VERSION 5.7 ;
  NOWIREEXTENSIONATPIN ON ;
  DIVIDERCHAR "/" ;
  BUSBITCHARS "[]" ;
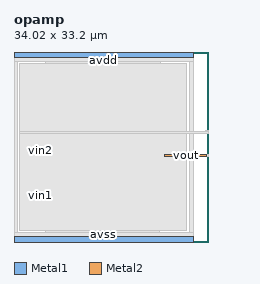
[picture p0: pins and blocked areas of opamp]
MACRO opamp
  CLASS BLOCK ;
  FOREIGN opamp ;
  ORIGIN 0.000 0.000 ;
  SIZE 34.020 BY 33.200 ;
  PIN avss
    USE GROUND ;
    PORT
      LAYER Metal1 ;
        RECT 0.000 0.000 31.400 1.000 ;
    END
  END avss
  PIN avdd
    USE POWER ;
    PORT
      LAYER Metal1 ;
        RECT 0.000 32.200 31.400 33.200 ;
    END
  END avdd
  PIN vout
    ANTENNADIFFAREA 10.568000 ;
    PORT
      LAYER Metal2 ;
        RECT 26.385 14.925 33.610 15.275 ;
    END
  END vout
  PIN vin2
    ANTENNAGATEAREA 5.000000 ;
    PORT
      LAYER Metal2 ;
        RECT 4.090 15.455 5.220 16.540 ;
    END
  END vin2
  PIN vin1
    ANTENNAGATEAREA 5.000000 ;
    PORT
      LAYER Metal2 ;
        RECT 3.935 7.435 5.225 8.720 ;
    END
  END vin1
  OBS
      LAYER Nwell ;
        RECT 13.490 26.500 17.875 26.540 ;
        RECT 21.060 26.500 25.000 26.540 ;
        RECT 13.490 26.410 25.000 26.500 ;
        RECT 12.860 26.300 25.000 26.410 ;
        RECT 6.790 23.690 25.000 26.300 ;
        RECT 6.790 22.520 25.020 23.690 ;
        RECT 6.790 15.800 24.960 22.520 ;
        RECT 6.790 15.200 14.145 15.800 ;
      LAYER Pwell ;
        RECT 6.300 4.180 9.800 14.280 ;
        RECT 10.215 7.070 13.715 14.170 ;
        RECT 14.045 7.090 17.545 14.190 ;
        RECT 17.735 4.215 21.235 13.315 ;
        RECT 21.495 4.290 24.995 14.390 ;
      LAYER Metal1 ;
        RECT 5.585 26.410 25.645 32.200 ;
        RECT 6.110 26.085 25.260 26.410 ;
        RECT 6.110 25.885 18.150 26.085 ;
        RECT 6.110 25.180 7.205 25.885 ;
        RECT 8.050 25.415 9.030 25.645 ;
        RECT 7.665 25.180 7.895 25.240 ;
        RECT 4.090 15.455 5.220 16.540 ;
        RECT 6.110 16.325 7.895 25.180 ;
        RECT 9.185 16.530 9.415 25.240 ;
        RECT 9.875 25.200 10.105 25.885 ;
        RECT 10.950 25.415 11.930 25.645 ;
        RECT 12.775 25.400 18.150 25.885 ;
        RECT 19.175 25.845 20.355 25.850 ;
        RECT 18.995 25.615 20.355 25.845 ;
        RECT 20.125 25.440 20.355 25.615 ;
        RECT 18.610 25.400 18.840 25.440 ;
        RECT 10.565 25.200 10.795 25.240 ;
        RECT 6.110 15.615 7.205 16.325 ;
        RECT 7.665 16.260 7.895 16.325 ;
        RECT 8.385 16.235 8.750 16.260 ;
        RECT 9.140 16.235 9.420 16.530 ;
        RECT 8.385 16.085 9.420 16.235 ;
        RECT 8.050 15.955 9.420 16.085 ;
        RECT 9.875 16.335 10.830 25.200 ;
        RECT 12.085 16.935 12.315 25.240 ;
        RECT 12.775 24.550 18.850 25.400 ;
        RECT 20.125 24.600 20.360 25.440 ;
        RECT 12.775 23.815 18.150 24.550 ;
        RECT 18.610 24.460 18.840 24.550 ;
        RECT 19.295 24.295 19.780 24.540 ;
        RECT 20.120 24.460 20.360 24.600 ;
        RECT 20.120 24.295 20.355 24.460 ;
        RECT 19.295 24.285 20.355 24.295 ;
        RECT 18.995 24.065 20.355 24.285 ;
        RECT 18.995 24.055 19.975 24.065 ;
        RECT 20.820 23.815 25.260 26.085 ;
        RECT 12.775 23.690 25.260 23.815 ;
        RECT 12.775 22.375 25.315 23.690 ;
        RECT 12.775 22.285 24.775 22.375 ;
        RECT 12.775 21.550 14.275 22.285 ;
        RECT 15.120 21.815 16.100 22.045 ;
        RECT 16.640 21.815 17.620 22.045 ;
        RECT 18.160 21.815 19.140 22.045 ;
        RECT 19.680 21.815 20.660 22.045 ;
        RECT 21.200 21.815 22.180 22.045 ;
        RECT 22.720 21.815 23.700 22.045 ;
        RECT 14.735 21.550 14.965 21.640 ;
        RECT 12.775 21.400 14.965 21.550 ;
        RECT 12.775 20.835 15.195 21.400 ;
        RECT 12.030 16.410 12.445 16.935 ;
        RECT 12.775 16.900 14.965 20.835 ;
        RECT 16.255 18.050 16.485 21.640 ;
        RECT 17.775 21.355 18.005 21.640 ;
        RECT 17.660 20.790 18.255 21.355 ;
        RECT 16.160 17.560 16.550 18.050 ;
        RECT 8.050 15.855 9.030 15.955 ;
        RECT 9.875 15.615 10.105 16.335 ;
        RECT 10.565 16.260 10.795 16.335 ;
        RECT 11.140 16.085 11.545 16.270 ;
        RECT 12.085 16.260 12.315 16.410 ;
        RECT 12.775 16.215 14.275 16.900 ;
        RECT 14.735 16.860 14.965 16.900 ;
        RECT 15.345 16.685 15.760 16.985 ;
        RECT 16.255 16.860 16.485 17.560 ;
        RECT 16.715 16.685 17.250 16.905 ;
        RECT 17.775 16.860 18.005 20.790 ;
        RECT 19.295 18.050 19.525 21.640 ;
        RECT 20.815 21.380 21.045 21.640 ;
        RECT 20.675 20.815 21.270 21.380 ;
        RECT 19.170 17.565 19.595 18.050 ;
        RECT 18.440 16.870 18.825 16.910 ;
        RECT 18.400 16.685 18.865 16.870 ;
        RECT 19.295 16.860 19.525 17.565 ;
        RECT 19.925 16.685 20.335 16.925 ;
        RECT 20.815 16.860 21.045 20.815 ;
        RECT 22.335 18.025 22.565 21.640 ;
        RECT 23.855 21.600 24.085 21.640 ;
        RECT 24.545 21.600 24.775 22.285 ;
        RECT 22.205 17.580 22.695 18.025 ;
        RECT 21.495 16.685 21.905 16.925 ;
        RECT 22.335 16.860 22.565 17.580 ;
        RECT 23.850 16.950 24.800 21.600 ;
        RECT 23.025 16.685 23.475 16.925 ;
        RECT 23.855 16.860 24.085 16.950 ;
        RECT 15.120 16.455 16.100 16.685 ;
        RECT 16.640 16.455 17.620 16.685 ;
        RECT 18.160 16.455 19.140 16.685 ;
        RECT 19.680 16.455 20.660 16.685 ;
        RECT 21.200 16.455 22.180 16.685 ;
        RECT 22.720 16.455 23.700 16.685 ;
        RECT 15.360 16.445 15.745 16.455 ;
        RECT 18.440 16.445 18.825 16.455 ;
        RECT 19.925 16.445 20.335 16.455 ;
        RECT 21.495 16.445 21.905 16.455 ;
        RECT 23.025 16.445 23.475 16.455 ;
        RECT 24.545 16.215 24.775 16.950 ;
        RECT 10.950 15.855 11.930 16.085 ;
        RECT 12.775 16.000 24.775 16.215 ;
        RECT 12.775 15.615 13.005 16.000 ;
        RECT 14.045 15.985 24.775 16.000 ;
        RECT 6.110 15.385 13.005 15.615 ;
        RECT 6.110 15.370 7.090 15.385 ;
        RECT 25.310 14.690 26.385 15.695 ;
        RECT 6.485 14.090 9.615 14.095 ;
        RECT 6.485 14.075 10.575 14.090 ;
        RECT 5.550 13.985 10.575 14.075 ;
        RECT 13.455 14.005 14.560 14.075 ;
        RECT 13.455 13.985 17.360 14.005 ;
        RECT 5.550 13.865 17.360 13.985 ;
        RECT 5.550 13.070 6.715 13.865 ;
        RECT 9.385 13.775 17.360 13.865 ;
        RECT 9.385 13.755 14.560 13.775 ;
        RECT 7.560 13.395 8.540 13.625 ;
        RECT 7.755 13.235 8.270 13.395 ;
        RECT 7.175 13.070 7.405 13.220 ;
        RECT 3.940 8.720 5.215 8.730 ;
        RECT 3.935 7.435 5.225 8.720 ;
        RECT 5.550 5.300 7.405 13.070 ;
        RECT 5.550 4.695 6.715 5.300 ;
        RECT 7.175 5.240 7.405 5.300 ;
        RECT 7.805 5.295 8.190 13.235 ;
        RECT 8.695 11.345 8.925 13.220 ;
        RECT 8.540 10.895 8.980 11.345 ;
        RECT 7.805 5.065 8.355 5.295 ;
        RECT 8.695 5.240 8.925 10.895 ;
        RECT 9.385 7.485 10.630 13.755 ;
        RECT 11.475 13.285 12.455 13.515 ;
        RECT 11.090 11.360 11.320 13.110 ;
        RECT 12.610 12.325 12.840 13.110 ;
        RECT 12.545 12.000 12.950 12.325 ;
        RECT 11.090 10.880 11.535 11.360 ;
        RECT 11.090 8.130 11.320 10.880 ;
        RECT 11.615 7.955 12.145 8.290 ;
        RECT 12.610 8.130 12.840 12.000 ;
        RECT 11.475 7.725 12.455 7.955 ;
        RECT 13.300 7.505 14.560 13.755 ;
        RECT 15.305 13.305 16.285 13.535 ;
        RECT 14.920 11.345 15.150 13.130 ;
        RECT 16.440 12.555 16.670 13.130 ;
        RECT 16.355 12.040 16.790 12.555 ;
        RECT 14.920 10.895 15.360 11.345 ;
        RECT 14.920 8.150 15.150 10.895 ;
        RECT 15.525 7.975 16.035 8.165 ;
        RECT 16.440 8.150 16.670 12.040 ;
        RECT 15.305 7.745 16.285 7.975 ;
        RECT 15.525 7.735 16.035 7.745 ;
        RECT 17.130 7.505 17.360 13.775 ;
        RECT 21.680 13.975 24.810 14.205 ;
        RECT 13.300 7.485 17.360 7.505 ;
        RECT 9.385 7.440 17.360 7.485 ;
        RECT 17.920 12.900 21.050 13.130 ;
        RECT 21.680 13.120 21.910 13.975 ;
        RECT 22.755 13.505 23.735 13.735 ;
        RECT 22.370 13.120 22.600 13.330 ;
        RECT 17.920 12.060 18.150 12.900 ;
        RECT 18.995 12.430 19.975 12.660 ;
        RECT 18.610 12.060 18.840 12.255 ;
        RECT 17.920 7.440 18.840 12.060 ;
        RECT 20.130 11.720 20.360 12.255 ;
        RECT 20.030 11.230 20.440 11.720 ;
        RECT 9.385 5.505 18.840 7.440 ;
        RECT 7.560 4.835 8.540 5.065 ;
        RECT 5.505 4.595 6.780 4.695 ;
        RECT 9.385 4.630 18.150 5.505 ;
        RECT 18.610 5.275 18.840 5.505 ;
        RECT 19.305 5.100 19.695 5.355 ;
        RECT 20.130 5.275 20.360 11.230 ;
        RECT 18.995 4.870 19.975 5.100 ;
        RECT 19.305 4.860 19.695 4.870 ;
        RECT 20.820 4.695 21.050 12.900 ;
        RECT 21.665 5.455 22.600 13.120 ;
        RECT 23.890 5.600 24.120 13.330 ;
        RECT 23.350 5.515 24.150 5.600 ;
        RECT 21.680 4.705 21.910 5.455 ;
        RECT 22.370 5.350 22.600 5.455 ;
        RECT 22.950 5.175 24.150 5.515 ;
        RECT 22.755 5.000 24.150 5.175 ;
        RECT 22.755 4.945 23.735 5.000 ;
        RECT 24.580 4.705 24.810 13.975 ;
        RECT 21.680 4.695 24.810 4.705 ;
        RECT 20.820 4.630 25.415 4.695 ;
        RECT 9.385 4.595 25.415 4.630 ;
        RECT 5.505 1.000 25.415 4.595 ;
      LAYER Metal2 ;
        RECT 6.730 25.610 19.730 25.995 ;
        RECT 4.470 15.285 5.220 15.455 ;
        RECT 4.470 14.900 5.230 15.285 ;
        RECT 4.620 10.480 5.005 14.900 ;
        RECT 6.730 13.610 7.115 25.610 ;
        RECT 19.345 24.115 19.730 25.610 ;
        RECT 14.600 20.835 24.530 21.365 ;
        RECT 16.160 17.980 16.550 18.050 ;
        RECT 19.170 17.980 19.595 18.050 ;
        RECT 22.205 17.980 22.695 18.025 ;
        RECT 16.130 17.960 22.695 17.980 ;
        RECT 16.130 17.630 24.570 17.960 ;
        RECT 16.160 17.560 16.550 17.630 ;
        RECT 19.170 17.565 19.595 17.630 ;
        RECT 22.090 17.610 24.570 17.630 ;
        RECT 22.205 17.580 22.695 17.610 ;
        RECT 22.275 17.535 22.625 17.580 ;
        RECT 12.030 16.865 12.445 16.935 ;
        RECT 14.155 16.865 14.570 16.915 ;
        RECT 15.345 16.870 15.760 16.985 ;
        RECT 16.715 16.870 17.250 16.905 ;
        RECT 15.320 16.865 17.250 16.870 ;
        RECT 18.405 16.865 18.865 16.910 ;
        RECT 19.925 16.865 20.335 16.925 ;
        RECT 21.495 16.865 21.905 16.925 ;
        RECT 23.025 16.865 23.475 16.925 ;
        RECT 12.005 16.480 23.475 16.865 ;
        RECT 12.030 16.410 12.445 16.480 ;
        RECT 14.155 16.430 14.570 16.480 ;
        RECT 15.345 16.460 15.760 16.480 ;
        RECT 8.445 16.260 8.725 16.290 ;
        RECT 8.385 16.115 8.750 16.260 ;
        RECT 11.140 16.115 11.545 16.270 ;
        RECT 8.385 16.105 11.545 16.115 ;
        RECT 12.100 16.105 12.885 16.115 ;
        RECT 8.385 15.920 12.885 16.105 ;
        RECT 8.445 15.835 12.885 15.920 ;
        RECT 11.185 15.825 12.885 15.835 ;
        RECT 7.835 13.660 8.220 13.720 ;
        RECT 7.805 13.610 8.220 13.660 ;
        RECT 6.730 13.225 8.220 13.610 ;
        RECT 7.805 13.175 8.220 13.225 ;
        RECT 7.835 13.170 8.220 13.175 ;
        RECT 12.605 12.325 12.885 15.825 ;
        RECT 16.785 12.555 17.170 16.480 ;
        RECT 18.405 16.445 18.865 16.480 ;
        RECT 19.925 16.445 20.335 16.480 ;
        RECT 21.495 16.445 21.905 16.480 ;
        RECT 23.025 16.445 23.475 16.480 ;
        RECT 18.445 16.435 18.820 16.445 ;
        RECT 22.275 15.275 22.625 15.295 ;
        RECT 24.220 15.275 24.570 17.610 ;
        RECT 25.700 15.275 26.110 15.360 ;
        RECT 33.675 15.275 34.020 15.325 ;
        RECT 16.355 12.490 17.170 12.555 ;
        RECT 12.545 12.000 12.950 12.325 ;
        RECT 16.350 12.105 17.170 12.490 ;
        RECT 20.900 14.925 26.385 15.275 ;
        RECT 33.610 14.925 34.020 15.275 ;
        RECT 16.355 12.040 16.790 12.105 ;
        RECT 20.030 11.650 20.440 11.720 ;
        RECT 20.900 11.650 21.250 14.925 ;
        RECT 25.700 14.870 26.110 14.925 ;
        RECT 33.675 14.875 34.020 14.925 ;
        RECT 8.540 11.300 8.980 11.345 ;
        RECT 11.100 11.300 11.535 11.360 ;
        RECT 14.925 11.300 15.360 11.345 ;
        RECT 20.030 11.300 21.250 11.650 ;
        RECT 8.540 10.940 15.460 11.300 ;
        RECT 20.030 11.230 20.440 11.300 ;
        RECT 8.540 10.895 8.980 10.940 ;
        RECT 11.100 10.880 11.535 10.940 ;
        RECT 14.925 10.895 15.360 10.940 ;
        RECT 15.585 10.480 15.970 10.490 ;
        RECT 4.620 10.095 15.970 10.480 ;
        RECT 11.615 7.835 12.145 8.290 ;
        RECT 15.585 8.165 15.970 10.095 ;
        RECT 4.440 6.850 4.850 7.435 ;
        RECT 11.675 6.850 12.085 7.835 ;
        RECT 15.525 7.730 16.035 8.165 ;
        RECT 4.440 6.445 12.085 6.850 ;
        RECT 4.440 6.440 7.840 6.445 ;
        RECT 8.390 6.440 12.085 6.445 ;
        RECT 7.895 5.305 8.305 5.390 ;
        RECT 23.000 5.305 23.410 5.605 ;
        RECT 7.895 4.895 23.410 5.305 ;
        RECT 7.895 4.845 8.305 4.895 ;
      LAYER Metal3 ;
        RECT 14.170 18.955 33.990 19.340 ;
        RECT 14.170 16.865 14.555 18.955 ;
        RECT 14.105 16.480 14.620 16.865 ;
        RECT 33.625 14.925 34.020 15.275 ;
      LAYER Metal4 ;
        RECT 0.000 31.600 31.400 32.200 ;
        RECT 0.000 1.600 0.600 31.600 ;
        RECT 30.600 15.275 31.400 31.600 ;
        RECT 33.555 19.370 33.940 19.390 ;
        RECT 33.480 18.930 34.020 19.370 ;
        RECT 33.555 18.905 33.940 18.930 ;
        RECT 33.675 15.275 34.020 15.325 ;
        RECT 30.600 14.925 34.020 15.275 ;
        RECT 30.600 1.600 31.400 14.925 ;
        RECT 33.675 14.875 34.020 14.925 ;
        RECT 0.000 1.000 31.400 1.600 ;
      LAYER Metal5 ;
        RECT 1.000 19.370 30.200 31.200 ;
        RECT 33.530 19.370 33.970 19.420 ;
        RECT 1.000 18.930 33.970 19.370 ;
        RECT 1.000 2.000 30.200 18.930 ;
        RECT 33.530 18.880 33.970 18.930 ;
  END
END opamp
END LIBRARY

